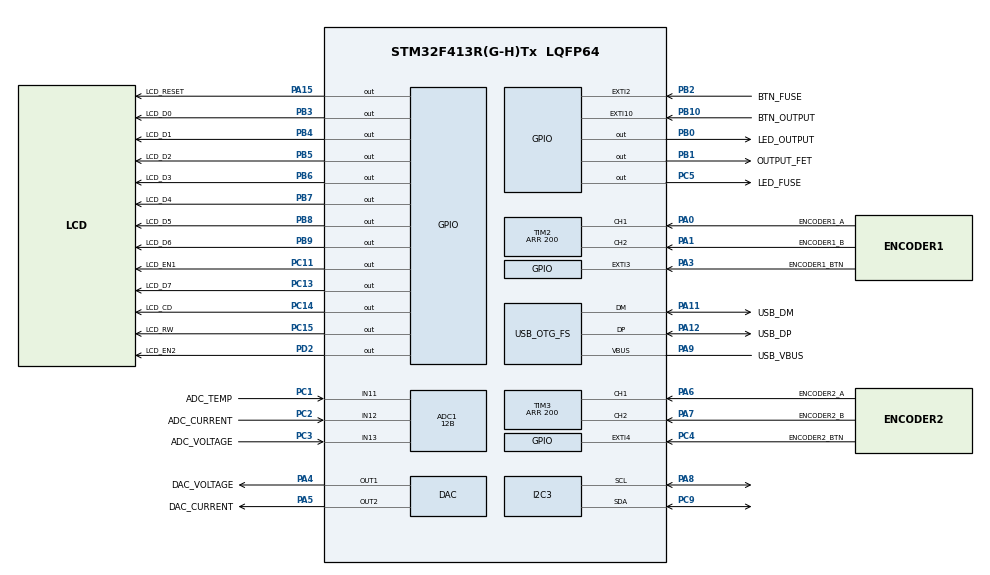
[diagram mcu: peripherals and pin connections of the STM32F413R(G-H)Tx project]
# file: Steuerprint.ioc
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ADC1.Channel-0\#ChannelRegularConversion=ADC_CHANNEL_11
ADC1.Channel-1\#ChannelRegularConversion=ADC_CHANNEL_12
ADC1.Channel-2\#ChannelRegularConversion=ADC_CHANNEL_13
ADC1.ClockPrescaler=ADC_CLOCK_SYNC_PCLK_DIV4
ADC1.ContinuousConvMode=ENABLE
ADC1.DMAContinuousRequests=ENABLE
ADC1.DataAlign=ADC_DATAALIGN_RIGHT
ADC1.DiscontinuousConvMode=DISABLE
ADC1.EOCSelection=ADC_EOC_SINGLE_CONV
ADC1.EnableAnalogWatchDog=false
ADC1.ExternalTrigConv=ADC_SOFTWARE_START
ADC1.ExternalTrigConvEdge=ADC_EXTERNALTRIGCONVEDGE_NONE
ADC1.InjNumberOfConversion=0
ADC1.NbrOfConversion=3
ADC1.NbrOfConversionFlag=1
ADC1.Rank-0\#ChannelRegularConversion=1
ADC1.Rank-1\#ChannelRegularConversion=2
ADC1.Rank-2\#ChannelRegularConversion=3
ADC1.Resolution=ADC_RESOLUTION_12B
ADC1.SamplingTime-0\#ChannelRegularConversion=ADC_SAMPLETIME_480CYCLES
ADC1.SamplingTime-1\#ChannelRegularConversion=ADC_SAMPLETIME_480CYCLES
ADC1.SamplingTime-2\#ChannelRegularConversion=ADC_SAMPLETIME_480CYCLES
ADC1.ScanConvMode=ENABLE
ADC1.master=1
DAC.DAC_OutputBuffer=DAC_OUTPUTBUFFER_DISABLE
DAC.DAC_OutputBuffer2=DAC_OUTPUTBUFFER_DISABLE
DAC.DAC_Trigger=DAC_TRIGGER_T6_TRGO
DAC.DAC_Trigger2=DAC_TRIGGER_T6_TRGO
Dma.ADC1.2.Direction=DMA_PERIPH_TO_MEMORY
Dma.ADC1.2.FIFOMode=DMA_FIFOMODE_DISABLE
Dma.ADC1.2.Instance=DMA2_Stream0
Dma.ADC1.2.MemDataAlignment=DMA_MDATAALIGN_HALFWORD
Dma.ADC1.2.MemInc=DMA_MINC_ENABLE
Dma.ADC1.2.Mode=DMA_CIRCULAR
Dma.ADC1.2.PeriphDataAlignment=DMA_PDATAALIGN_HALFWORD
Dma.ADC1.2.PeriphInc=DMA_PINC_DISABLE
Dma.ADC1.2.Priority=DMA_PRIORITY_VERY_HIGH
Dma.DAC1.0.Direction=DMA_MEMORY_TO_PERIPH
Dma.DAC1.0.FIFOMode=DMA_FIFOMODE_DISABLE
Dma.DAC1.0.Instance=DMA1_Stream5
Dma.DAC1.0.MemDataAlignment=DMA_MDATAALIGN_HALFWORD
Dma.DAC1.0.MemInc=DMA_MINC_DISABLE
Dma.DAC1.0.Mode=DMA_CIRCULAR
Dma.DAC1.0.PeriphDataAlignment=DMA_PDATAALIGN_HALFWORD
Dma.DAC1.0.PeriphInc=DMA_PINC_DISABLE
Dma.DAC1.0.Priority=DMA_PRIORITY_HIGH
Dma.DAC2.1.Direction=DMA_MEMORY_TO_PERIPH
Dma.DAC2.1.FIFOMode=DMA_FIFOMODE_DISABLE
Dma.DAC2.1.Instance=DMA1_Stream6
Dma.DAC2.1.MemDataAlignment=DMA_MDATAALIGN_HALFWORD
Dma.DAC2.1.MemInc=DMA_MINC_DISABLE
Dma.DAC2.1.Mode=DMA_CIRCULAR
Dma.DAC2.1.PeriphDataAlignment=DMA_PDATAALIGN_HALFWORD
Dma.DAC2.1.PeriphInc=DMA_PINC_DISABLE
Dma.DAC2.1.Priority=DMA_PRIORITY_HIGH
Dma.Request0=DAC1
Dma.Request1=DAC2
Dma.Request2=ADC1
Mcu.Family=STM32F4
Mcu.Name=STM32F413R(G-H)Tx
Mcu.Package=LQFP64
NVIC.DMA1_Stream5_IRQn=true\:0\:0\:false\:false\:true\:true
NVIC.DMA1_Stream6_IRQn=true\:0\:0\:false\:false\:true\:true
NVIC.DMA2_Stream0_IRQn=true\:0\:0\:false\:false\:true\:true
NVIC.EXTI15_10_IRQn=true\:0\:0\:false\:false\:false\:true
NVIC.EXTI2_IRQn=true\:0\:0\:false\:false\:false\:true
NVIC.EXTI3_IRQn=true\:0\:0\:false\:false\:false\:true
NVIC.EXTI4_IRQn=true\:0\:0\:false\:false\:false\:true
NVIC.OTG_FS_IRQn=true\:0\:0\:false\:false\:true\:true
NVIC.PriorityGroup=NVIC_PRIORITYGROUP_4
PA0.GPIO_Label=ENCODER1_A
PA0.GPIO_ModeDefaultPP=GPIO_MODE_AF_OD
PA0.Signal=S_TIM2_CH1_ETR
PA1.GPIO_Label=ENCODER1_B
PA1.GPIO_ModeDefaultPP=GPIO_MODE_AF_OD
PA1.Signal=S_TIM2_CH2
PA11.GPIO_Label=USB_DM
PA11.Mode=Device_Only
PA11.Signal=USB_OTG_FS_DM
PA12.GPIO_Label=USB_DP
PA12.Mode=Device_Only
PA12.Signal=USB_OTG_FS_DP
PA13.GPIO_Label=SWDIO
PA13.Mode=Serial_Wire
PA13.Signal=SYS_JTMS-SWDIO
PA14.GPIO_Label=SWCLK
PA14.Mode=Serial_Wire
PA14.Signal=SYS_JTCK-SWCLK
PA15.GPIO_Label=LCD_RESET
PA15.Signal=GPIO_Output
PA3.GPIO_Label=ENCODER1_BTN
PA3.Signal=GPXTI3
PA4.GPIO_Label=DAC_VOLTAGE
PA4.Signal=SharedAnalog_PA4
PA5.GPIO_Label=DAC_CURRENT
PA5.Signal=SharedAnalog_PA5
PA6.GPIO_Label=ENCODER2_A
PA6.GPIO_ModeDefaultPP=GPIO_MODE_AF_OD
PA6.Signal=S_TIM3_CH1
PA7.GPIO_Label=ENCODER2_B
PA7.GPIO_ModeDefaultPP=GPIO_MODE_AF_OD
PA7.Signal=S_TIM3_CH2
PA8.Mode=I2C
PA8.Signal=I2C3_SCL
PA9.GPIO_Label=USB_VBUS
PA9.Mode=Activate_VBUS
PA9.Signal=USB_OTG_FS_VBUS
PB0.GPIO_Label=LED_OUTPUT
PB0.Signal=GPIO_Output
PB1.GPIO_Label=OUTPUT_FET
PB1.Signal=GPIO_Output
PB10.GPIO_Label=BTN_OUTPUT
PB10.Signal=GPXTI10
PB2.GPIO_Label=BTN_FUSE
PB2.Signal=GPXTI2
PB3.GPIO_Label=LCD_D0
PB3.Signal=GPIO_Output
PB4.GPIO_Label=LCD_D1
PB4.Signal=GPIO_Output
PB5.GPIO_Label=LCD_D2
PB5.Signal=GPIO_Output
PB6.GPIO_Label=LCD_D3
PB6.Signal=GPIO_Output
PB7.GPIO_Label=LCD_D4
PB7.Signal=GPIO_Output
PB8.GPIO_Label=LCD_D5
PB8.Signal=GPIO_Output
PB9.GPIO_Label=LCD_D6
PB9.Signal=GPIO_Output
PC1.GPIO_Label=ADC_TEMP
PC1.Signal=SharedAnalog_PC1
PC11.GPIO_Label=LCD_EN1
PC11.Signal=GPIO_Output
PC13.GPIO_Label=LCD_D7
PC13.Signal=GPIO_Output
PC14-OSC32_IN.GPIO_Label=LCD_CD
PC14-OSC32_IN.Signal=GPIO_Output
PC15-OSC32_OUT.GPIO_Label=LCD_RW
PC15-OSC32_OUT.Signal=GPIO_Output
PC2.GPIO_Label=ADC_CURRENT
PC2.Signal=SharedAnalog_PC2
PC3.GPIO_Label=ADC_VOLTAGE
PC3.Signal=SharedAnalog_PC3
PC4.GPIO_Label=ENCODER2_BTN
PC4.Signal=GPXTI4
PC5.GPIO_Label=LED_FUSE
PC5.Signal=GPIO_Output
PC9.Mode=I2C
PC9.Signal=I2C3_SDA
PD2.GPIO_Label=LCD_EN2
PD2.Signal=GPIO_Output
PH0\ -\ OSC_IN.Mode=HSE-External-Oscillator
PH0\ -\ OSC_IN.Signal=RCC_OSC_IN
PH1\ -\ OSC_OUT.Mode=HSE-External-Oscillator
PH1\ -\ OSC_OUT.Signal=RCC_OSC_OUT
ProjectManager.HeapSize=0x2000
ProjectManager.StackSize=0x4000
ProjectManager.TargetToolchain=MDK-ARM V5
RCC.AHBFreq_Value=100000000
RCC.APB1CLKDivider=RCC_HCLK_DIV2
RCC.APB1Freq_Value=50000000
RCC.APB1TimFreq_Value=100000000
RCC.APB2Freq_Value=100000000
RCC.APB2TimFreq_Value=100000000
RCC.CortexFreq_Value=100000000
RCC.HCLKFreq_Value=100000000
RCC.HSE_VALUE=16000000
RCC.PLLI2SM=8
RCC.PLLI2SN=72
RCC.PLLI2SQ=3
RCC.PLLM=8
RCC.PLLN=100
RCC.PLLQ=4
RCC.SYSCLKFreq_VALUE=100000000
RCC.SYSCLKSource=RCC_SYSCLKSOURCE_PLLCLK
RCC.USBCLockSelection=RCC_CLK48CLKSOURCE_PLLI2SQ
RCC.USBFreq_Value=48000000
RCC.VCOOutputFreq_Value=200000000
SH.S_TIM2_CH1_ETR.0=TIM2_CH1,Encoder_Interface
SH.S_TIM2_CH2.0=TIM2_CH2,Encoder_Interface
SH.S_TIM3_CH1.0=TIM3_CH1,Encoder_Interface
SH.S_TIM3_CH2.0=TIM3_CH2,Encoder_Interface
SH.SharedAnalog_PA4.0=GPIO_Analog
SH.SharedAnalog_PA4.1=DAC_OUT1,DAC_OUT1
SH.SharedAnalog_PA5.0=GPIO_Analog
SH.SharedAnalog_PA5.1=DAC_OUT2,DAC_OUT2
SH.SharedAnalog_PC1.0=GPIO_Analog
SH.SharedAnalog_PC1.1=ADC1_IN11,IN11
SH.SharedAnalog_PC2.0=GPIO_Analog
SH.SharedAnalog_PC2.1=ADC1_IN12,IN12
SH.SharedAnalog_PC3.0=GPIO_Analog
SH.SharedAnalog_PC3.1=ADC1_IN13,IN13
TIM2.IC1Filter=1
TIM2.IC2Filter=1
TIM2.Period=200
TIM3.IC1Filter=1
TIM3.IC2Filter=1
TIM3.Period=200
TIM6.Period=64000
TIM6.Prescaler=0
TIM6.TIM_MasterOutputTrigger=TIM_TRGO_UPDATE
TIM7.Period=55535
TIM7.Prescaler=10000
USB_DEVICE.CLASS_NAME_FS=CDC
USB_DEVICE.LANGID_STRING=1031
USB_DEVICE.MANUFACTURER_STRING=TFBern
USB_DEVICE.PRODUCT_STRING_CDC_FS=Netzger\u00E4t
USB_DEVICE.USBD_SELF_POWERED=1
USB_DEVICE.USBD_SUPPORT_USER_STRING=1
USB_DEVICE.VirtualMode=Cdc
USB_DEVICE.VirtualModeFS=Cdc_FS
USB_OTG_FS.VirtualMode=Device_Only
USB_OTG_FS.battery_charging_enable=DISABLE
VP_RTC_VS_RTC_Activate.Mode=RTC_Enabled
VP_TIM6_VS_ClockSourceINT.Mode=Enable_Timer
VP_TIM7_VS_ClockSourceINT.Mode=Enable_Timer
VP_USB_DEVICE_VS_USB_DEVICE_CDC_FS.Mode=CDC_FS
board=Steuerprint

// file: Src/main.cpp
/**
  ******************************************************************************
  * File Name          : main.c
  * Description        : Main program body
  ******************************************************************************
  * This notice applies to any and all portions of this file
  * that are not between comment pairs USER CODE BEGIN and
  * USER CODE END. Other portions of this file, whether
  * inserted by the user or by software development tools
  * are owned by their respective copyright owners.
  *
  * Copyright (c) 2017 STMicroelectronics International N.V.
  * All rights reserved.
  *
  * Redistribution and use in source and binary forms, with or without
  * modification, are permitted, provided that the following conditions are met:
  *
  * 1. Redistribution of source code must retain the above copyright notice,
  *    this list of conditions and the following disclaimer.
  * 2. Redistributions in binary form must reproduce the above copyright notice,
  *    this list of conditions and the following disclaimer in the documentation
  *    and/or other materials provided with the distribution.
  * 3. Neither the name of STMicroelectronics nor the names of other
  *    contributors to this software may be used to endorse or promote products
  *    derived from this software without specific written permission.
  * 4. This software, including modifications and/or derivative works of this
  *    software, must execute solely and exclusively on microcontroller or
  *    microprocessor devices manufactured by or for STMicroelectronics.
  * 5. Redistribution and use of this software other than as permitted under
  *    this license is void and will automatically terminate your rights under
  *    this license.
  *
  * THIS SOFTWARE IS PROVIDED BY STMICROELECTRONICS AND CONTRIBUTORS "AS IS"
  * AND ANY EXPRESS, IMPLIED OR STATUTORY WARRANTIES, INCLUDING, BUT NOT
  * LIMITED TO, THE IMPLIED WARRANTIES OF MERCHANTABILITY, FITNESS FOR A
  * PARTICULAR PURPOSE AND NON-INFRINGEMENT OF THIRD PARTY INTELLECTUAL PROPERTY
  * RIGHTS ARE DISCLAIMED TO THE FULLEST EXTENT PERMITTED BY LAW. IN NO EVENT
  * SHALL STMICROELECTRONICS OR CONTRIBUTORS BE LIABLE FOR ANY DIRECT, INDIRECT,
  * INCIDENTAL, SPECIAL, EXEMPLARY, OR CONSEQUENTIAL DAMAGES (INCLUDING, BUT NOT
  * LIMITED TO, PROCUREMENT OF SUBSTITUTE GOODS OR SERVICES; LOSS OF USE, DATA,
  * OR PROFITS; OR BUSINESS INTERRUPTION) HOWEVER CAUSED AND ON ANY THEORY OF
  * LIABILITY, WHETHER IN CONTRACT, STRICT LIABILITY, OR TORT (INCLUDING
  * NEGLIGENCE OR OTHERWISE) ARISING IN ANY WAY OUT OF THE USE OF THIS SOFTWARE,
  * EVEN IF ADVISED OF THE POSSIBILITY OF SUCH DAMAGE.
  *
  ******************************************************************************
  */

extern "C" {
	#include "stm32f4xx_hal.h"
	#include "main.h"
	#include "adc.h"
	#include "dac.h"
	#include "dma.h"
	#include "rtc.h"
	#include "i2c.h"
	#include "tim.h"
	#include "usb_device.h"
	#include "gpio.h"

	/* USER CODE BEGIN Includes */
	#include "display.h"
	#include "peripherals.h"
    #include "Settings.h"

    #include <math.h>
}

#include "os.h"

#define sign(i) ((i > 0) - (i < 0))

/* USER CODE END Includes */

/* USER CODE BEGIN PV */
OS os;
/* Private variables ---------------------------------------------------------*/
/* USER CODE END PV */

void SystemClock_Config(void);

/* USER CODE BEGIN PFP */
/* Private function prototypes -----------------------------------------------*/
void fuseButton(void) {
	HAL_GPIO_TogglePin(GPIOC, GPIO_PIN_5);
	//Output ausschalten
}

void outputButton(void) {
	HAL_GPIO_TogglePin(GPIOB, GPIO_PIN_0);
	HAL_GPIO_WritePin(OUTPUT_FET_GPIO_Port, OUTPUT_FET_Pin, HAL_GPIO_ReadPin(GPIOB, GPIO_PIN_0) == 1 ? GPIO_PIN_RESET : GPIO_PIN_SET);
}

void encoderATurned(int8_t steps) {
	if(TIM7->CNT<((abs(steps) * 500 / FAST_STEP_FREQUENCY)))
		OS::targetI += -steps * AMPS_PER_STEP * FAST_MULTIPLICATOR;
	else
		OS::targetI += -steps * AMPS_PER_STEP / 2;

	TIM7->CNT = 0;
	HAL_TIM_Base_Start(&htim7);

	if(OS::targetI < 0.0f) OS::targetI = 0.0f;
	else if(OS::targetI > IOUTMAX) OS::targetI = IOUTMAX;
}

void encoderBTurned(int8_t steps) {
	if(TIM7->CNT < ((abs(steps) * 500 / FAST_STEP_FREQUENCY)))
		OS::targetU += -steps * VOLTS_PER_STEP * FAST_MULTIPLICATOR;
	else
		OS::targetU += -steps * VOLTS_PER_STEP / 2;

	TIM7->CNT = 0;
	HAL_TIM_Base_Start(&htim7);

	if(os.targetU < 0.0f) OS::targetU = 0.0f;
	else if(os.targetU > UOUTMAX) OS::targetU = UOUTMAX;
}

void encoderAButton(void) {

}

void encoderBButton(void) {

}
/* USER CODE END PFP */

int main(void) {
    static uint32_t adcReadCnt = 0;

  /* MCU Configuration----------------------------------------------------------*/

  /* Reset of all peripherals, Initializes the Flash interface and the Systick. */
  HAL_Init();

  /* Configure the system clock */
  SystemClock_Config();

  /* Initialize all configured peripherals */
  MX_GPIO_Init();
  MX_DMA_Init();
  MX_ADC1_Init();
  MX_DAC_Init();
  MX_TIM2_Init();
  MX_TIM3_Init();
  MX_USB_DEVICE_Init();
  MX_RTC_Init();
  MX_TIM6_Init();
  MX_I2C3_Init();
  MX_TIM7_Init();

  /* USER CODE BEGIN 2 */
  initCallbacks();
  initUsDelay();
  initDisplay();
  initADC(&hadc1);
  initDAC(&hdac, &htim6);
  initEncoder(&htim2, &htim3);
  /* USER CODE END 2 */

  /* Infinite loop */
  /* USER CODE BEGIN WHILE */
  setBrightness(100);
  setContrast(95);
  /* USER CODE END WHILE */

  /* USER CODE BEGIN 3 */

  addOutputButtonCallback(&outputButton);
  addFuseButtonCallback(&fuseButton);
  addEncoderATurnedCallback(&encoderATurned);
  addEncoderBTurnedCallback(&encoderBTurned);
  addEncoderAButtonCallback(&encoderAButton);
  addEncoderBButtonCallback(&encoderBButton);

  os.onInit();

  while(os.running) {
    if(adcReadCnt++ >= 10) {
        OS::actualU = getADCValue(U_IST);
        OS::actualI = getADCValue(I_IST);

        if(OS::actualU < 0)
            OS::actualU = 0;
        if(OS::actualI < 0)
            OS::actualI = 0;
        if(OS::actualU > 99.9)
            OS::actualU = 99.9;
        if(OS::actualI > 1999)
            OS::actualI = 1999;

        adcReadCnt = 0;
    }
    setDACValue(U_SOLL, OS::targetU);
    setDACValue(I_SOLL, OS::targetI);

    handleEncoderCallbacks();
	os.mainEntry();
  }

  os.onShutdown();

  /* USER CODE END 3 */

}

/** System Clock Configuration
*/
void SystemClock_Config(void)
{

  RCC_OscInitTypeDef RCC_OscInitStruct;
  RCC_ClkInitTypeDef RCC_ClkInitStruct;
  RCC_PeriphCLKInitTypeDef PeriphClkInitStruct;

    /**Configure the main internal regulator output voltage
    */
  __HAL_RCC_PWR_CLK_ENABLE();

  __HAL_PWR_VOLTAGESCALING_CONFIG(PWR_REGULATOR_VOLTAGE_SCALE1);

    /**Initializes the CPU, AHB and APB busses clocks
    */
  RCC_OscInitStruct.OscillatorType = RCC_OSCILLATORTYPE_LSI|RCC_OSCILLATORTYPE_HSE;
  RCC_OscInitStruct.HSEState = RCC_HSE_ON;
  RCC_OscInitStruct.LSIState = RCC_LSI_ON;
  RCC_OscInitStruct.PLL.PLLState = RCC_PLL_ON;
  RCC_OscInitStruct.PLL.PLLSource = RCC_PLLSOURCE_HSE;
  RCC_OscInitStruct.PLL.PLLM = 16;
  RCC_OscInitStruct.PLL.PLLN = 160;
  RCC_OscInitStruct.PLL.PLLP = RCC_PLLP_DIV2;
  RCC_OscInitStruct.PLL.PLLQ = 4;
  RCC_OscInitStruct.PLL.PLLR = 2;
  if (HAL_RCC_OscConfig(&RCC_OscInitStruct) != HAL_OK)
  {
    _Error_Handler(__FILE__, __LINE__);
  }

    /**Initializes the CPU, AHB and APB busses clocks
    */
  RCC_ClkInitStruct.ClockType = RCC_CLOCKTYPE_HCLK|RCC_CLOCKTYPE_SYSCLK
                              |RCC_CLOCKTYPE_PCLK1|RCC_CLOCKTYPE_PCLK2;
  RCC_ClkInitStruct.SYSCLKSource = RCC_SYSCLKSOURCE_PLLCLK;
  RCC_ClkInitStruct.AHBCLKDivider = RCC_SYSCLK_DIV1;
  RCC_ClkInitStruct.APB1CLKDivider = RCC_HCLK_DIV2;
  RCC_ClkInitStruct.APB2CLKDivider = RCC_HCLK_DIV1;

  if (HAL_RCC_ClockConfig(&RCC_ClkInitStruct, FLASH_LATENCY_3) != HAL_OK)
  {
    _Error_Handler(__FILE__, __LINE__);
  }

  PeriphClkInitStruct.PeriphClockSelection = RCC_PERIPHCLK_RTC|RCC_PERIPHCLK_CLK48;
  PeriphClkInitStruct.PLLI2S.PLLI2SN = 192;
  PeriphClkInitStruct.PLLI2S.PLLI2SM = 16;
  PeriphClkInitStruct.PLLI2S.PLLI2SR = 2;
  PeriphClkInitStruct.PLLI2S.PLLI2SQ = 4;
  PeriphClkInitStruct.RTCClockSelection = RCC_RTCCLKSOURCE_LSI;
  PeriphClkInitStruct.Clk48ClockSelection = RCC_CLK48CLKSOURCE_PLLI2SQ;
  PeriphClkInitStruct.PLLI2SSelection = RCC_PLLI2SCLKSOURCE_PLLSRC;
  if (HAL_RCCEx_PeriphCLKConfig(&PeriphClkInitStruct) != HAL_OK)
  {
    _Error_Handler(__FILE__, __LINE__);
  }

    /**Configure the Systick interrupt time
    */
  HAL_SYSTICK_Config(HAL_RCC_GetHCLKFreq()/1000);

    /**Configure the Systick
    */
  HAL_SYSTICK_CLKSourceConfig(SYSTICK_CLKSOURCE_HCLK);

  /* SysTick_IRQn interrupt configuration */
  HAL_NVIC_SetPriority(SysTick_IRQn, 0, 0);
}

void _Error_Handler(char * file, int line)
{
  while(1)
  {
  }
}

/************************ (C) COPYRIGHT STMicroelectronics *****END OF FILE****/
